VERSION 5.8 ;
BUSBITCHARS "[]" ;
DIVIDERCHAR "/" ;
UNITS
 DATABASE MICRONS 1000 ;
END UNITS
MANUFACTURINGGRID 0.001 ;
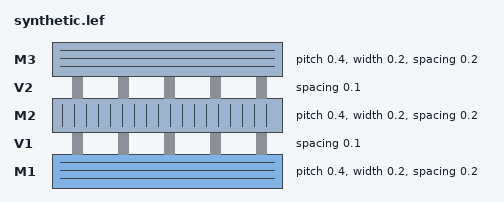
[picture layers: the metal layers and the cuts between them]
LAYER M1
 TYPE ROUTING ;
 DIRECTION HORIZONTAL ;
 PITCH 0.4 ;
 WIDTH 0.2 ;
 SPACING 0.2 ;
END M1
LAYER V1
 TYPE CUT ;
 SPACING 0.1 ;
END V1
LAYER M2
 TYPE ROUTING ;
 DIRECTION VERTICAL ;
 PITCH 0.4 ;
 WIDTH 0.2 ;
 SPACING 0.2 ;
END M2
LAYER V2
 TYPE CUT ;
 SPACING 0.1 ;
END V2
LAYER M3
 TYPE ROUTING ;
 DIRECTION HORIZONTAL ;
 PITCH 0.4 ;
 WIDTH 0.2 ;
 SPACING 0.2 ;
END M3
SITE CORE
 CLASS CORE ;
 SYMMETRY Y ;
 SIZE 1 BY 2 ;
END CORE
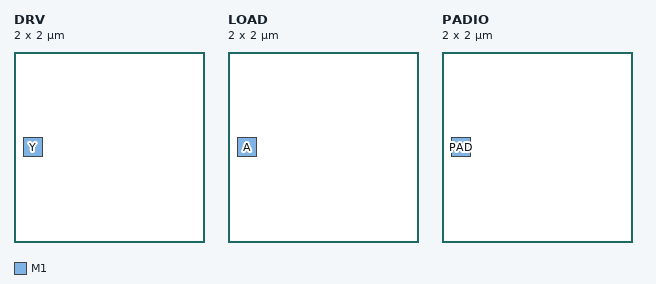
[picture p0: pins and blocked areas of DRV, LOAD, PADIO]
MACRO DRV
 CLASS CORE ;
 ORIGIN 0 0 ;
 SIZE 2 BY 2 ;
 SYMMETRY X Y ;
 SITE CORE ;
 PIN Y
  DIRECTION OUTPUT ;
  USE SIGNAL ;
  PORT
   LAYER M1 ;
   RECT 0.1 0.9 0.3 1.1 ;
  END
 END Y
END DRV
MACRO LOAD
 CLASS CORE ;
 ORIGIN 0 0 ;
 SIZE 2 BY 2 ;
 SYMMETRY X Y ;
 SITE CORE ;
 PIN A
  DIRECTION INPUT ;
  USE SIGNAL ;
  PORT
   LAYER M1 ;
   RECT 0.1 0.9 0.3 1.1 ;
  END
 END A
END LOAD
MACRO PADIO
 CLASS CORE ;
 ORIGIN 0 0 ;
 SIZE 2 BY 2 ;
 SYMMETRY X Y ;
 SITE CORE ;
 PIN PAD
  DIRECTION INOUT ;
  USE SIGNAL ;
  PORT
   LAYER M1 ;
   RECT 0.1 0.9 0.3 1.1 ;
  END
 END PAD
END PADIO
END LIBRARY
